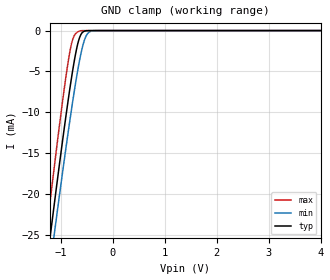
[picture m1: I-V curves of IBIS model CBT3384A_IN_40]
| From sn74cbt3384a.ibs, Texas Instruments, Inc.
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[Model]   CBT3384A_IN_40
Model_type  Input
Vinl=0.8
Vinh=2.0
| variable   typ   min   max
C_comp   1.03pF   0.87pF   1.16pF
[Temperature Range]   40   100   -40
| Ambient temperature   25   85   -40
[Voltage range]   4   4   4
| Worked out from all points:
|   GND clamp passes 1 mA (typ) near -0.64 V on its own axis
[GND Clamp]
| CBT3384A_IN_40
|   Voltage   I(typ)   I(min)   I(max)
-4V       -176mA     -174.5mA   -179.3mA
-1.28V    -29.15mA   -32.56mA   -24.99mA
-1.245V   -27.36mA   -30.84mA   -23.11mA
-1.18V    -24.07mA   -27.66mA   -19.66mA
-1.12V    -21.07mA   -24.75mA   -16.52mA
-935mV    -12.12mA   -16.01mA   -7.284mA
-830mV    -7.388mA   -11.29mA   -2.826mA
-750mV    -4.148mA   -7.89mA    -763uA
-655mV    -1.231mA   -4.262mA   -110.4uA
-530mV    -51.34uA   -937.2uA   -218.8nA
-390mV    -699.5nA   -41.64uA   -797.5pA
4V        31.19pA    1.76nA     26.57pA
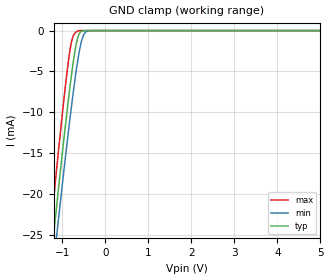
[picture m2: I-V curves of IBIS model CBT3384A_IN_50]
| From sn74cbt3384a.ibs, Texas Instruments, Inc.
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[Model]   CBT3384A_IN_50
Model_type  Input
Vinl=0.8
Vinh=2.0
| variable   typ   min   max
C_comp   1.13pF   0.85pF   2.68pF
[Temperature Range]   40   100   -40
| Ambient temperature   25   85   -40
[Voltage range]   5   4.5   5.5
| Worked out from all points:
|   GND clamp passes 1 mA (typ) near -0.64 V on its own axis
[GND Clamp]
| CBT3384A_IN_50
|   Voltage   I(typ)   I(min)   I(max)
-5V       -231.3mA   -228mA     -237.2mA
-1.29V    -29.66mA   -33.06mA   -25.52mA
-1.25V    -27.62mA   -31.09mA   -23.38mA
-1.175V   -23.82mA   -27.41mA   -19.4mA
-1.105V   -20.33mA   -24.03mA   -15.74mA
-925mV    -11.65mA   -15.55mA   -6.819mA
-820mV    -6.96mA    -10.85mA   -2.477mA
-750mV    -4.148mA   -7.89mA    -763uA
-635mV    -837.4uA   -3.586mA   -56.8uA
-520mV    -38.16uA   -784.6uA   -146.4nA
-375mV    -439.5nA   -28.48uA   -438.5pA
5V        38.55pA    1.779nA    29.22pA
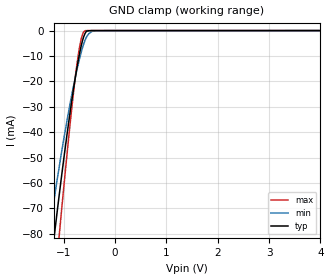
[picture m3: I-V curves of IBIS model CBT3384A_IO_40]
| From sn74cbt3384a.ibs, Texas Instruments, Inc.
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[Model]   CBT3384A_IO_40
Model_type  Terminator
| variable   typ   min   max
C_comp   3.06pF   2.67pF   3.63pF
| C_tri-state   3.06pF   2.67pF   3.63pF
[Temperature Range]   40   100   -40
| Ambient temperature   25   85   -40
[Voltage range]   4   4   4
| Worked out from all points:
|   GND clamp passes 1 mA (typ) near -0.58 V on its own axis
[GND Clamp]
| CBT3384A_IO_40
|   Voltage   I(typ)   I(min)   I(max)
-4V       -1.73A     -1.7A      -1.641A
-1.315V   -103.5mA   -84.37mA   -131.5mA
-1.265V   -94.59mA   -77mA      -119.9mA
-1.2V     -83.27mA   -68.02mA   -105.1mA
-1.13V    -71.42mA   -58.79mA   -89.53mA
-1.055V   -59.15mA   -49.32mA   -73.22mA
-885mV    -33.25mA   -29.57mA   -38.25mA
-740mV    -14.21mA   -15.1mA    -12.69mA
-660mV    -5.942mA   -8.504mA   -3.256mA
-585mV    -1.074mA   -3.772mA   -45.55uA
-370mV    -651.7nA   -39.64uA   -8.679nA
4V        43.74pA    1.964nA    23.55pA
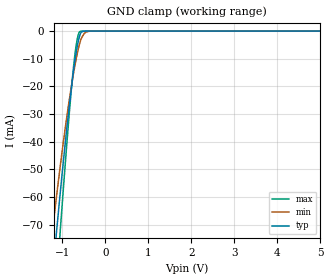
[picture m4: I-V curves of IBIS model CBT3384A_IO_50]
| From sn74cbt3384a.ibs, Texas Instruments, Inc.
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[Model]   CBT3384A_IO_50
Model_type  Terminator
| variable   typ   min   max
C_comp   3.15pF   2.61pF   5.74pF
| C_tri-state   3.15pF   2.61pF   5.74pF
[Temperature Range]   40   100   -40
| Ambient temperature   25   85   -40
[Voltage range]   5   4.5   5.5
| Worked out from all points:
|   GND clamp passes 1 mA (typ) near -0.58 V on its own axis
[GND Clamp]
| CBT3384A_IO_50
|   Voltage   I(typ)   I(min)   I(max)
-5V       -2.154A    -2.151A    -2.001A
-1.285V   -98.14mA   -79.88mA   -124.5mA
-1.215V   -85.85mA   -70.06mA   -108.5mA
-1.13V    -71.42mA   -58.79mA   -89.53mA
-1.045V   -57.55mA   -48.09mA   -71.08mA
-840mV    -26.95mA   -24.81mA   -29.66mA
-735mV    -13.63mA   -14.65mA   -11.96mA
-655mV    -5.513mA   -8.137mA   -2.855mA
-580mV    -888.3uA   -3.526mA   -37.33uA
-500mV    -41.58uA   -986.1uA   -1.54uA
-360mV    -475.4nA   -30.12uA   -5.828nA
5V        56.57pA    1.978nA    30.78pA
